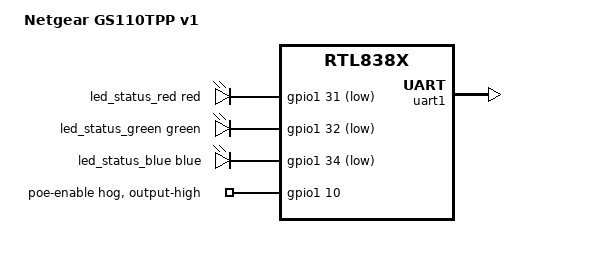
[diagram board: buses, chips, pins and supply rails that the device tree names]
// SPDX-License-Identifier: GPL-2.0-or-later

#include "rtl8380_netgear_gigabit.dtsi"
#include <dt-bindings/leds/common.h>

/ {
	compatible = "netgear,gs110tpp-v1", "realtek,rtl838x-soc";
	model = "Netgear GS110TPP v1";

	aliases {
		led-boot = &led_status_green;
		led-failsafe = &led_status_red;
		led-running = &led_status_green;
		led-upgrade = &led_status_blue;
	};

	leds {
		compatible = "gpio-leds";

		led_status_red: led-0 {
			color = <LED_COLOR_ID_RED>;
			function = LED_FUNCTION_STATUS;
			gpios = <&gpio1 31 GPIO_ACTIVE_LOW>;
		};

		led_status_green: led-1 {
			color = <LED_COLOR_ID_GREEN>;
			function = LED_FUNCTION_STATUS;
			gpios = <&gpio1 32 GPIO_ACTIVE_LOW>;
		};

		led_status_blue: led-2 {
			color = <LED_COLOR_ID_BLUE>;
			function = LED_FUNCTION_STATUS;
			gpios = <&gpio1 34 GPIO_ACTIVE_LOW>;
		};
	};
};

&gpio1 {
	poe-enable {
		gpio-hog;
		gpios = <10 GPIO_ACTIVE_HIGH>;
		output-high;
		line-name = "poe-enable";
	};
};

&firmware {
	openwrt,ih-magic = <0x4e474520>;
};

&uart1 {
	status = "okay";
};

&mdio_bus0 {
	PHY_C22(16, 16)
	PHY_C22(17, 17)
};

&switch0 {
	ethernet-ports {
		SWITCH_PORT_SDS(16, 9, 2, 0, qsgmii)
		SWITCH_PORT_SDS(17, 10, 2, 1, qsgmii)
	};
};
